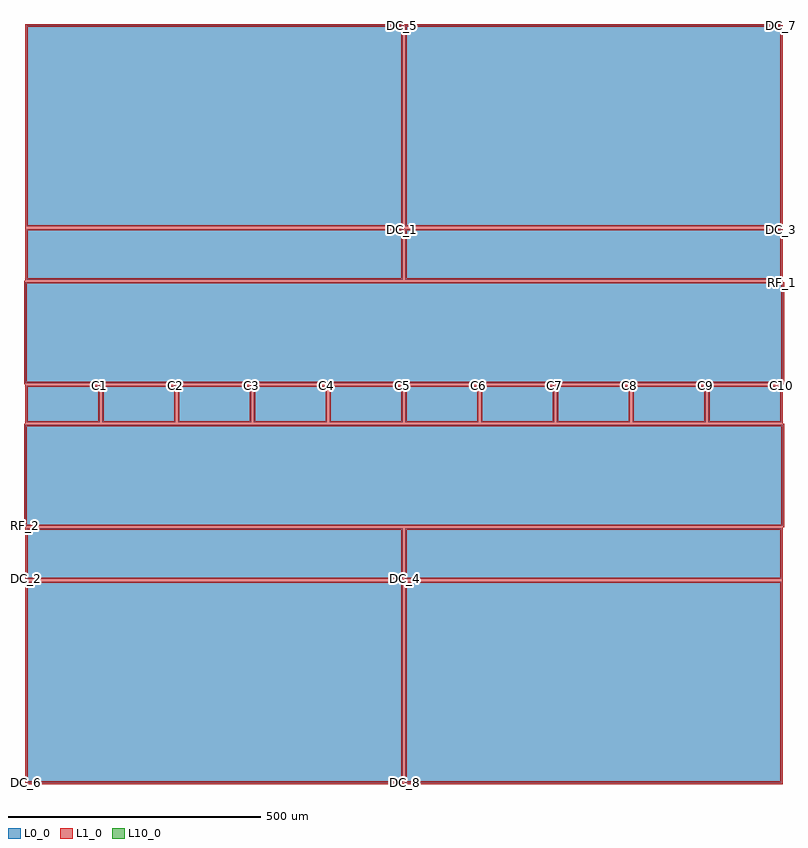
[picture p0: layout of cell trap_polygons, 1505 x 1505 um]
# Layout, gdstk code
import gdstk
lib = gdstk.Library(unit=1e-6, precision=1e-09)
def P(c, l, *ps):  # polygons
    for p in ps: c.add(gdstk.Polygon(p, *l))
L0_0 = (0, 0)
L1_0 = (1, 0)
L10_0 = (10, 0)

trap_polygons = lib.new_cell('trap_polygons')
P(trap_polygons, L0_0, [(2.5,-750),(2.5,-351.5),(747.5,-351.5),(747.5,-750),(2.5,-750)],
  [(747.5,750),(747.5,351.5),(2.5,351.5),(2.5,750),(747.5,750)],
  [(-747.5,-750),(-747.5,-351.5),(-2.5,-351.5),(-2.5,-750),(-747.5,-750)],
  [(-2.5,750),(-2.5,351.5),(-747.5,351.5),(-747.5,750),(-2.5,750)],
  [(2.5,-346.5),(2.5,-246.5),(747.5,-246.5),(747.5,-346.5),(2.5,-346.5)],
  [(747.5,346.5),(747.5,246.5),(2.5,246.5),(2.5,346.5),(747.5,346.5)],
  [(-747.5,-346.5),(-747.5,-246.5),(-2.5,-246.5),(-2.5,-346.5),(-747.5,-346.5)],
  [(-2.5,346.5),(-2.5,246.5),(-747.5,246.5),(-747.5,346.5),(-2.5,346.5)],
  [(747.5,36.5),(747.5,-36.5),(602.5,-36.5),(602.5,36.5),(747.5,36.5)],
  [(597.5,36.5),(597.5,-36.5),(452.5,-36.5),(452.5,36.5),(597.5,36.5)],
  [(447.5,36.5),(447.5,-36.5),(302.5,-36.5),(302.5,36.5),(447.5,36.5)],
  [(297.5,36.5),(297.5,-36.5),(152.5,-36.5),(152.5,36.5),(297.5,36.5)],
  [(147.5,36.5),(147.5,-36.5),(2.5,-36.5),(2.5,36.5),(147.5,36.5)],
  [(-2.5,36.5),(-2.5,-36.5),(-147.5,-36.5),(-147.5,36.5),(-2.5,36.5)],
  [(-152.5,36.5),(-152.5,-36.5),(-297.5,-36.5),(-297.5,36.5),(-152.5,36.5)],
  [(-302.5,36.5),(-302.5,-36.5),(-447.5,-36.5),(-447.5,36.5),(-302.5,36.5)],
  [(-452.5,36.5),(-452.5,-36.5),(-597.5,-36.5),(-597.5,36.5),(-452.5,36.5)],
  [(-602.5,36.5),(-602.5,-36.5),(-747.5,-36.5),(-747.5,36.5),(-602.5,36.5)],
  [(-750,-241.5),(-750,-41.5),(750,-41.5),(750,-241.5),(-750,-241.5)],
  [(750,241.5),(750,41.5),(-750,41.5),(-750,241.5),(750,241.5)])
P(trap_polygons, L1_0, [(0,-750),(5,-750),(5,-354),(745,-354),(745,-747.5),(2.5,-747.5),(2.5,-752.5),(750,-752.5),(750,-349),(0,-349)],
  [(750,750),(745,750),(745,354),(5,354),(5,747.5),(747.5,747.5),(747.5,752.5),(0,752.5),(0,349),(750,349)],
  [(-750,-750),(-745,-750),(-745,-354),(-5,-354),(-5,-747.5),(-747.5,-747.5),(-747.5,-752.5),(0,-752.5),(0,-349),(-750,-349)],
  [(0,750),(-5,750),(-5,354),(-745,354),(-745,747.5),(-2.5,747.5),(-2.5,752.5),(-750,752.5),(-750,349),(0,349)],
  [(0,-346.5),(5,-346.5),(5,-249),(745,-249),(745,-344),(2.5,-344),(2.5,-349),(750,-349),(750,-244),(0,-244)],
  [(750,346.5),(745,346.5),(745,249),(5,249),(5,344),(747.5,344),(747.5,349),(0,349),(0,244),(750,244)],
  [(-750,-346.5),(-745,-346.5),(-745,-249),(-5,-249),(-5,-344),(-747.5,-344),(-747.5,-349),(0,-349),(0,-244),(-750,-244)],
  [(0,346.5),(-5,346.5),(-5,249),(-745,249),(-745,344),(-2.5,344),(-2.5,349),(-750,349),(-750,244),(0,244)],
  [(750,36.5),(745,36.5),(745,-34),(605,-34),(605,34),(747.5,34),(747.5,39),(600,39),(600,-39),(750,-39)],
  [(600,36.5),(595,36.5),(595,-34),(455,-34),(455,34),(597.5,34),(597.5,39),(450,39),(450,-39),(600,-39)],
  [(450,36.5),(445,36.5),(445,-34),(305,-34),(305,34),(447.5,34),(447.5,39),(300,39),(300,-39),(450,-39)],
  [(300,36.5),(295,36.5),(295,-34),(155,-34),(155,34),(297.5,34),(297.5,39),(150,39),(150,-39),(300,-39)],
  [(150,36.5),(145,36.5),(145,-34),(5,-34),(5,34),(147.5,34),(147.5,39),(0,39),(0,-39),(150,-39)],
  [(0,36.5),(-5,36.5),(-5,-34),(-145,-34),(-145,34),(-2.5,34),(-2.5,39),(-150,39),(-150,-39),(0,-39)],
  [(-150,36.5),(-155,36.5),(-155,-34),(-295,-34),(-295,34),(-152.5,34),(-152.5,39),(-300,39),(-300,-39),(-150,-39)],
  [(-300,36.5),(-305,36.5),(-305,-34),(-445,-34),(-445,34),(-302.5,34),(-302.5,39),(-450,39),(-450,-39),(-300,-39)],
  [(-450,36.5),(-455,36.5),(-455,-34),(-595,-34),(-595,34),(-452.5,34),(-452.5,39),(-600,39),(-600,-39),(-450,-39)],
  [(-600,36.5),(-605,36.5),(-605,-34),(-745,-34),(-745,34),(-602.5,34),(-602.5,39),(-750,39),(-750,-39),(-600,-39)],
  [(-752.5,-241.5),(-747.5,-241.5),(-747.5,-44),(747.5,-44),(747.5,-239),(-750,-239),(-750,-244),(752.5,-244),(752.5,-39),(-752.5,-39)],
  [(752.5,241.5),(747.5,241.5),(747.5,44),(-747.5,44),(-747.5,239),(750,239),(750,244),(-752.5,244),(-752.5,39),(752.5,39)])
P(trap_polygons, L10_0, [(0,0),(0,0),(0,0),(0,0)])
trap_polygons.add(gdstk.Label('DC_8', (2.5,-750), layer=2, texttype=0))
trap_polygons.add(gdstk.Label('DC_7', (747.5,750), layer=2, texttype=0))
trap_polygons.add(gdstk.Label('DC_6', (-747.5,-750), layer=2, texttype=0))
trap_polygons.add(gdstk.Label('DC_5', (-2.5,750), layer=2, texttype=0))
trap_polygons.add(gdstk.Label('DC_4', (2.5,-346.5), layer=2, texttype=0))
trap_polygons.add(gdstk.Label('DC_3', (747.5,346.5), layer=2, texttype=0))
trap_polygons.add(gdstk.Label('DC_2', (-747.5,-346.5), layer=2, texttype=0))
trap_polygons.add(gdstk.Label('DC_1', (-2.5,346.5), layer=2, texttype=0))
trap_polygons.add(gdstk.Label('C10', (747.5,36.5), layer=2, texttype=0))
trap_polygons.add(gdstk.Label('C9', (597.5,36.5), layer=2, texttype=0))
trap_polygons.add(gdstk.Label('C8', (447.5,36.5), layer=2, texttype=0))
trap_polygons.add(gdstk.Label('C7', (297.5,36.5), layer=2, texttype=0))
trap_polygons.add(gdstk.Label('C6', (147.5,36.5), layer=2, texttype=0))
trap_polygons.add(gdstk.Label('C5', (-2.5,36.5), layer=2, texttype=0))
trap_polygons.add(gdstk.Label('C4', (-152.5,36.5), layer=2, texttype=0))
trap_polygons.add(gdstk.Label('C3', (-302.5,36.5), layer=2, texttype=0))
trap_polygons.add(gdstk.Label('C2', (-452.5,36.5), layer=2, texttype=0))
trap_polygons.add(gdstk.Label('C1', (-602.5,36.5), layer=2, texttype=0))
trap_polygons.add(gdstk.Label('RF_2', (-750,-241.5), layer=2, texttype=0))
trap_polygons.add(gdstk.Label('RF_1', (750,241.5), layer=2, texttype=0))

lib.write_gds('trap_polygons.gds')
